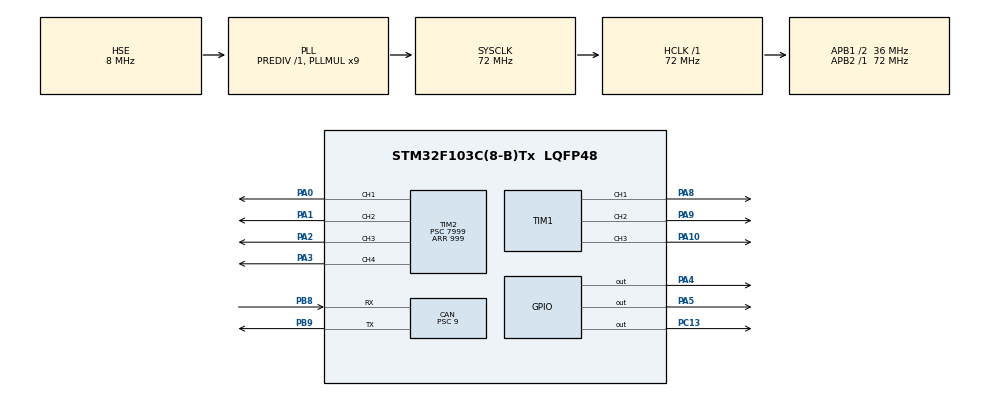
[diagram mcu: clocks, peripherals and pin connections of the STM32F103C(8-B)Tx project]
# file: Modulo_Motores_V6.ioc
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CAN.BS1=CAN_BS1_13TQ
CAN.BS2=CAN_BS2_2TQ
CAN.CalculateTimeBit=4000
CAN.CalculateTimeQuantum=250.0
CAN.Prescaler=9
Mcu.Family=STM32F1
Mcu.Name=STM32F103C(8-B)Tx
Mcu.Package=LQFP48
NVIC.PriorityGroup=NVIC_PRIORITYGROUP_4
NVIC.TIM2_IRQn=true\:0\:0\:false\:false\:true\:true\:true
NVIC.USB_LP_CAN1_RX0_IRQn=true\:0\:0\:false\:false\:true\:true\:true
PA0-WKUP.Signal=S_TIM2_CH1_ETR
PA1.Signal=S_TIM2_CH2
PA10.Signal=S_TIM1_CH3
PA2.Signal=S_TIM2_CH3
PA3.Signal=S_TIM2_CH4
PA4.Signal=GPIO_Output
PA5.Signal=GPIO_Output
PA8.Signal=S_TIM1_CH1
PA9.Signal=S_TIM1_CH2
PB8.Mode=Master
PB8.Signal=CAN_RX
PB9.Mode=Master
PB9.Signal=CAN_TX
PC13-TAMPER-RTC.Signal=GPIO_Output
PD0-OSC_IN.Mode=HSE-External-Oscillator
PD0-OSC_IN.Signal=RCC_OSC_IN
PD1-OSC_OUT.Mode=HSE-External-Oscillator
PD1-OSC_OUT.Signal=RCC_OSC_OUT
ProjectManager.HeapSize=0x200
ProjectManager.StackSize=0x400
ProjectManager.TargetToolchain=TrueSTUDIO
RCC.AHBFreq_Value=72000000
RCC.APB1CLKDivider=RCC_HCLK_DIV2
RCC.APB1Freq_Value=36000000
RCC.APB1TimFreq_Value=72000000
RCC.APB2Freq_Value=72000000
RCC.APB2TimFreq_Value=72000000
RCC.HCLKFreq_Value=72000000
RCC.PLLMUL=RCC_PLL_MUL9
RCC.PLLSourceVirtual=RCC_PLLSOURCE_HSE
RCC.SYSCLKFreq_VALUE=72000000
RCC.SYSCLKSource=RCC_SYSCLKSOURCE_PLLCLK
RCC.USBFreq_Value=72000000
SH.S_TIM1_CH1.0=TIM1_CH1,PWM Generation1 CH1
SH.S_TIM1_CH2.0=TIM1_CH2,PWM Generation2 CH2
SH.S_TIM1_CH3.0=TIM1_CH3,Output Compare3 CH3
SH.S_TIM2_CH1_ETR.0=TIM2_CH1,PWM Generation1 CH1
SH.S_TIM2_CH2.0=TIM2_CH2,PWM Generation2 CH2
SH.S_TIM2_CH3.0=TIM2_CH3,PWM Generation3 CH3
SH.S_TIM2_CH4.0=TIM2_CH4,PWM Generation4 CH4
TIM1.Channel-Output\ Compare3\ CH3=TIM_CHANNEL_3
TIM1.Channel-PWM\ Generation1\ CH1=TIM_CHANNEL_1
TIM1.Channel-PWM\ Generation2\ CH2=TIM_CHANNEL_2
TIM2.Channel-PWM\ Generation1\ CH1=TIM_CHANNEL_1
TIM2.Channel-PWM\ Generation2\ CH2=TIM_CHANNEL_2
TIM2.Channel-PWM\ Generation3\ CH3=TIM_CHANNEL_3
TIM2.Channel-PWM\ Generation4\ CH4=TIM_CHANNEL_4
TIM2.Period=999
TIM2.Prescaler=7999
VP_SYS_VS_ND.Mode=No_Debug
board=custom

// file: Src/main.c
/*

	 .d88888b.  8888888b.  8888888888 888b     d888 888     888  .d8888b.
	d88P" "Y88b 888   Y88b 888        8888b   d8888 888     888 d88P  Y88b
	888     888 888    888 888        88888b.d88888 888     888 Y88b.
	888     888 888   d88P 8888888    888Y88888P888 888     888  "Y888b.
	888     888 8888888P"  888        888 Y888P 888 888     888     "Y88b.
	888     888 888 T88b   888        888  Y8P  888 888     888       "888
	Y88b. .d88P 888  T88b  888        888   "   888 Y88b. .d88P Y88b  d88P
	 "Y88888P"  888   T88b 8888888888 888       888  "Y88888P"   "Y8888P"

  ******************************************************************************
  *        M  O  D  U  L  O     M  O  T  O  R  E  S  -  Versão 7   17/01/2020
  ******************************************************************************

	htim1, TIM_CHANNEL_1, -> Motor de propulsão R
	htim1, TIM_CHANNEL_2  -> Motor de propulsão L

	htim2, TIM_CHANNEL_1, -> Atuador 1
	htim2, TIM_CHANNEL_2, -> Atuador 2
	htim2, TIM_CHANNEL_3, -> Atuador 3
	htim2, TIM_CHANNEL_4, -> Atuador 4

	htim1, TIM_CHANNEL_3  -> LED

	Sensor RPM Motor = B10

	Excurção Máxima - 25 a 250 (0º a 180º) cada unidade é 0.8 graus
	Excurção Pratica - -60º / 0 / + 60º ( 37 / 112 / 187)

	CAN GPIO Configuration
    PB8  -> CAN_RX
    PB9  -> CAN_TX

    PA10  -> LED

	IDs
	0x003 => power on/off
	0x00a => RPM

/* USER CODE BEGIN Header */
/**
  ******************************************************************************
  * @file           : main.c
  * @brief          : Main program body
  ******************************************************************************
  * @attention
  *
  * <h2><center>&copy; Copyright (c) 2020 STMicroelectronics.
  * All rights reserved.</center></h2>
  *
  * This software component is licensed by ST under BSD 3-Clause license,
  * the "License"; You may not use this file except in compliance with the
  * License. You may obtain a copy of the License at:
  *                        opensource.org/licenses/BSD-3-Clause
  *
  ******************************************************************************
  */
/* USER CODE END Header */

#include "main.h"

CAN_HandleTypeDef hcan;

TIM_HandleTypeDef htim1;
TIM_HandleTypeDef htim2;

static CAN_TxHeaderTypeDef TxHeader;
static CAN_RxHeaderTypeDef RxHeader;
uint8_t TxData[8];
uint8_t RxData[8];
uint32_t TxMailbox;

void SystemClock_Config(void);
static void MX_GPIO_Init(void);
static void MX_TIM2_Init(void);
static void MX_CAN_Init(void);
static void MX_TIM1_Init(void);

int main(void)
{

  /* MCU Configuration--------------------------------------------------------*/

  /* Reset of all peripherals, Initializes the Flash interface and the Systick. */
  HAL_Init();
  SystemClock_Config();
  MX_GPIO_Init();
  MX_TIM2_Init();
  MX_CAN_Init();
  MX_TIM1_Init();

  HAL_TIM_Base_Start(&htim1);
  HAL_TIM_PWM_Start(&htim1,TIM_CHANNEL_1); // PWM_L
  HAL_TIM_PWM_Start(&htim1,TIM_CHANNEL_2); // PWM_R
  HAL_TIM_PWM_Start(&htim1,TIM_CHANNEL_3); // LED VERDE

  HAL_TIM_Base_Start(&htim2);
  HAL_TIM_PWM_Start(&htim2,TIM_CHANNEL_1); //A1
  HAL_TIM_PWM_Start(&htim2,TIM_CHANNEL_2); //A2
  HAL_TIM_PWM_Start(&htim2,TIM_CHANNEL_3); //A3
  HAL_TIM_PWM_Start(&htim2,TIM_CHANNEL_4); //A4

  /* Infinite loop */
  /* USER CODE BEGIN WHILE */
  int pwm=0;

  while (1)
  {

	  if (RxHeader.StdId == 0x003){ // green

			__HAL_TIM_SET_COMPARE(&htim2, TIM_CHANNEL_1, RxData[0]); //update pwm value
			__HAL_TIM_SET_COMPARE(&htim2, TIM_CHANNEL_2, RxData[1]); //update pwm value
			__HAL_TIM_SET_COMPARE(&htim2, TIM_CHANNEL_3, RxData[2]); //update pwm value
			__HAL_TIM_SET_COMPARE(&htim2, TIM_CHANNEL_4, RxData[3]); //update pwm value
			__HAL_TIM_SET_COMPARE(&htim1, TIM_CHANNEL_2, RxData[4]); //update pwm value
			HAL_Delay(5);  //hold for 400m
		  }

  }
  /* USER CODE END 3 */
}

void SystemClock_Config(void)
{
  RCC_OscInitTypeDef RCC_OscInitStruct = {0};
  RCC_ClkInitTypeDef RCC_ClkInitStruct = {0};

  /** Initializes the CPU, AHB and APB busses clocks
  */
  RCC_OscInitStruct.OscillatorType = RCC_OSCILLATORTYPE_HSE;
  RCC_OscInitStruct.HSEState = RCC_HSE_ON;
  RCC_OscInitStruct.HSEPredivValue = RCC_HSE_PREDIV_DIV1;
  RCC_OscInitStruct.HSIState = RCC_HSI_ON;
  RCC_OscInitStruct.PLL.PLLState = RCC_PLL_ON;
  RCC_OscInitStruct.PLL.PLLSource = RCC_PLLSOURCE_HSE;
  RCC_OscInitStruct.PLL.PLLMUL = RCC_PLL_MUL9;
  if (HAL_RCC_OscConfig(&RCC_OscInitStruct) != HAL_OK)
  {
    Error_Handler();
  }
  /** Initializes the CPU, AHB and APB busses clocks
  */
  RCC_ClkInitStruct.ClockType = RCC_CLOCKTYPE_HCLK|RCC_CLOCKTYPE_SYSCLK
                              |RCC_CLOCKTYPE_PCLK1|RCC_CLOCKTYPE_PCLK2;
  RCC_ClkInitStruct.SYSCLKSource = RCC_SYSCLKSOURCE_PLLCLK;
  RCC_ClkInitStruct.AHBCLKDivider = RCC_SYSCLK_DIV1;
  RCC_ClkInitStruct.APB1CLKDivider = RCC_HCLK_DIV2;
  RCC_ClkInitStruct.APB2CLKDivider = RCC_HCLK_DIV1;

  if (HAL_RCC_ClockConfig(&RCC_ClkInitStruct, FLASH_LATENCY_2) != HAL_OK)
  {
    Error_Handler();
  }
}

static void MX_CAN_Init(void)
{

  hcan.Instance = CAN1;
  hcan.Init.Prescaler = 9;
  hcan.Init.Mode = CAN_MODE_NORMAL;
  hcan.Init.SyncJumpWidth = CAN_SJW_1TQ;
  hcan.Init.TimeSeg1 = CAN_BS1_13TQ;
  hcan.Init.TimeSeg2 = CAN_BS2_2TQ;
  hcan.Init.TimeTriggeredMode = DISABLE;
  hcan.Init.AutoBusOff = DISABLE;
  hcan.Init.AutoWakeUp = DISABLE;
  hcan.Init.AutoRetransmission = DISABLE;
  hcan.Init.ReceiveFifoLocked = DISABLE;
  hcan.Init.TransmitFifoPriority = DISABLE;
  if (HAL_CAN_Init(&hcan) != HAL_OK)
  {
    Error_Handler();
  }

  if (HAL_CAN_ActivateNotification(&hcan, CAN_IT_RX_FIFO0_MSG_PENDING) != HAL_OK)
  {
	Error_Handler();
  }

  /* Configure the CAN Filter */
  CAN_FilterTypeDef  sFilterConfig;
  sFilterConfig.FilterBank = 0;
  sFilterConfig.FilterMode = CAN_FILTERMODE_IDMASK;
  sFilterConfig.FilterScale = CAN_FILTERSCALE_32BIT;
  sFilterConfig.FilterIdHigh     = 0x000<<5; //0x000
  sFilterConfig.FilterIdLow      = 0x0000;
  sFilterConfig.FilterMaskIdHigh = 0x700<<5; // mascara que filtra
  sFilterConfig.FilterMaskIdLow  = 0x0000;
  sFilterConfig.FilterFIFOAssignment = CAN_RX_FIFO0;
  sFilterConfig.FilterActivation = ENABLE;
  sFilterConfig.SlaveStartFilterBank = 14;
  if (HAL_CAN_ConfigFilter(&hcan, &sFilterConfig) != HAL_OK)
  {
    /* Filter configuration Error */
    Error_Handler();
  }

  /* Configure Transmission process */
  TxHeader.StdId = 0x001;
  TxHeader.ExtId = 0x001;
  TxHeader.RTR = CAN_RTR_DATA;
  TxHeader.IDE = CAN_ID_STD;
  TxHeader.DLC = 8;
  TxHeader.TransmitGlobalTime = DISABLE;

  /* Start the CAN peripheral */
  if (HAL_CAN_Start(&hcan) != HAL_OK)
  {
    /* Start Error */
    Error_Handler();
  }

}

static void MX_TIM1_Init(void)
{

  TIM_MasterConfigTypeDef sMasterConfig = {0};
  TIM_OC_InitTypeDef sConfigOC = {0};
  TIM_BreakDeadTimeConfigTypeDef sBreakDeadTimeConfig = {0};

  htim1.Instance = TIM1;
  htim1.Init.Prescaler = 11;
  htim1.Init.CounterMode = TIM_COUNTERMODE_UP;
  htim1.Init.Period = 300;
  htim1.Init.ClockDivision = TIM_CLOCKDIVISION_DIV1;
  htim1.Init.RepetitionCounter = 0;
  htim1.Init.AutoReloadPreload = TIM_AUTORELOAD_PRELOAD_DISABLE;
  if (HAL_TIM_PWM_Init(&htim1) != HAL_OK)
  {
    Error_Handler();
  }
  sMasterConfig.MasterOutputTrigger = TIM_TRGO_RESET;
  sMasterConfig.MasterSlaveMode = TIM_MASTERSLAVEMODE_DISABLE;
  if (HAL_TIMEx_MasterConfigSynchronization(&htim1, &sMasterConfig) != HAL_OK)
  {
    Error_Handler();
  }
  sConfigOC.OCMode = TIM_OCMODE_PWM1;
  sConfigOC.Pulse = 0;
  sConfigOC.OCPolarity = TIM_OCPOLARITY_HIGH;
  sConfigOC.OCNPolarity = TIM_OCNPOLARITY_HIGH;
  sConfigOC.OCFastMode = TIM_OCFAST_DISABLE;
  sConfigOC.OCIdleState = TIM_OCIDLESTATE_RESET;
  sConfigOC.OCNIdleState = TIM_OCNIDLESTATE_RESET;
  if (HAL_TIM_PWM_ConfigChannel(&htim1, &sConfigOC, TIM_CHANNEL_1) != HAL_OK)
  {
    Error_Handler();
  }
  if (HAL_TIM_PWM_ConfigChannel(&htim1, &sConfigOC, TIM_CHANNEL_2) != HAL_OK)
  {
    Error_Handler();
  }
  if (HAL_TIM_PWM_ConfigChannel(&htim1, &sConfigOC, TIM_CHANNEL_3) != HAL_OK)
  {
    Error_Handler();
  }
  sBreakDeadTimeConfig.OffStateRunMode = TIM_OSSR_DISABLE;
  sBreakDeadTimeConfig.OffStateIDLEMode = TIM_OSSI_DISABLE;
  sBreakDeadTimeConfig.LockLevel = TIM_LOCKLEVEL_OFF;
  sBreakDeadTimeConfig.DeadTime = 0;
  sBreakDeadTimeConfig.BreakState = TIM_BREAK_DISABLE;
  sBreakDeadTimeConfig.BreakPolarity = TIM_BREAKPOLARITY_HIGH;
  sBreakDeadTimeConfig.AutomaticOutput = TIM_AUTOMATICOUTPUT_DISABLE;
  if (HAL_TIMEx_ConfigBreakDeadTime(&htim1, &sBreakDeadTimeConfig) != HAL_OK)
  {
    Error_Handler();
  }
  HAL_TIM_MspPostInit(&htim1);

}

static void MX_TIM2_Init(void)
{

  TIM_MasterConfigTypeDef sMasterConfig = {0};
  TIM_OC_InitTypeDef sConfigOC = {0};

  htim2.Instance = TIM2;
  htim2.Init.Prescaler = 799;
  htim2.Init.CounterMode = TIM_COUNTERMODE_UP;
  htim2.Init.Period = 1800;
  htim2.Init.ClockDivision = TIM_CLOCKDIVISION_DIV1;
  htim2.Init.AutoReloadPreload = TIM_AUTORELOAD_PRELOAD_DISABLE;
  if (HAL_TIM_PWM_Init(&htim2) != HAL_OK)
  {
    Error_Handler();
  }
  sMasterConfig.MasterOutputTrigger = TIM_TRGO_RESET;
  sMasterConfig.MasterSlaveMode = TIM_MASTERSLAVEMODE_DISABLE;
  if (HAL_TIMEx_MasterConfigSynchronization(&htim2, &sMasterConfig) != HAL_OK)
  {
    Error_Handler();
  }
  sConfigOC.OCMode = TIM_OCMODE_PWM1;
  sConfigOC.Pulse = 0;
  sConfigOC.OCPolarity = TIM_OCPOLARITY_HIGH;
  sConfigOC.OCFastMode = TIM_OCFAST_DISABLE;
  if (HAL_TIM_PWM_ConfigChannel(&htim2, &sConfigOC, TIM_CHANNEL_1) != HAL_OK)
  {
    Error_Handler();
  }
  if (HAL_TIM_PWM_ConfigChannel(&htim2, &sConfigOC, TIM_CHANNEL_2) != HAL_OK)
  {
    Error_Handler();
  }
  if (HAL_TIM_PWM_ConfigChannel(&htim2, &sConfigOC, TIM_CHANNEL_3) != HAL_OK)
  {
    Error_Handler();
  }
  if (HAL_TIM_PWM_ConfigChannel(&htim2, &sConfigOC, TIM_CHANNEL_4) != HAL_OK)
  {
    Error_Handler();
  }
  HAL_TIM_MspPostInit(&htim2);

}

static void MX_GPIO_Init(void)
{
  GPIO_InitTypeDef GPIO_InitStruct = {0};

  /* GPIO Ports Clock Enable */
  __HAL_RCC_GPIOC_CLK_ENABLE();
  __HAL_RCC_GPIOD_CLK_ENABLE();
  __HAL_RCC_GPIOA_CLK_ENABLE();
  __HAL_RCC_GPIOB_CLK_ENABLE();

  /*Configure GPIO pin Output Level */
  HAL_GPIO_WritePin(GPIOC, GPIO_PIN_13, GPIO_PIN_SET);

  /*Configure GPIO pin : PC13 */
  GPIO_InitStruct.Pin = GPIO_PIN_13;
  GPIO_InitStruct.Mode = GPIO_MODE_OUTPUT_PP;
  GPIO_InitStruct.Pull = GPIO_NOPULL;
  GPIO_InitStruct.Speed = GPIO_SPEED_FREQ_LOW;
  HAL_GPIO_Init(GPIOC, &GPIO_InitStruct);

  /*Configure GPIO pin : PB12 */
  GPIO_InitStruct.Pin = GPIO_PIN_12;
  GPIO_InitStruct.Mode = GPIO_MODE_OUTPUT_PP;
  GPIO_InitStruct.Pull = GPIO_NOPULL;
  GPIO_InitStruct.Speed = GPIO_SPEED_FREQ_LOW;
  HAL_GPIO_Init(GPIOB, &GPIO_InitStruct);

  /*Configure GPIO pin : PB13 */
  GPIO_InitStruct.Pin = GPIO_PIN_13;
  GPIO_InitStruct.Mode = GPIO_MODE_OUTPUT_PP;
  GPIO_InitStruct.Pull = GPIO_NOPULL;
  GPIO_InitStruct.Speed = GPIO_SPEED_FREQ_LOW;
  HAL_GPIO_Init(GPIOB, &GPIO_InitStruct);

  /*Configure GPIO pin : PB14 */
  GPIO_InitStruct.Pin = GPIO_PIN_14;
  GPIO_InitStruct.Mode = GPIO_MODE_OUTPUT_PP;
  GPIO_InitStruct.Pull = GPIO_NOPULL;
  GPIO_InitStruct.Speed = GPIO_SPEED_FREQ_LOW;
  HAL_GPIO_Init(GPIOB, &GPIO_InitStruct);

}

void HAL_CAN_RxFifo0MsgPendingCallback(CAN_HandleTypeDef *hcan)
{
  //HAL_GPIO_TogglePin(GPIOC,GPIO_PIN_13);
  /* Get RX message */
  if (HAL_CAN_GetRxMessage(hcan, CAN_RX_FIFO0, &RxHeader, RxData) != HAL_OK)
  {

    Error_Handler();
  }
}

void Error_Handler(void)
{
  /* USER CODE BEGIN Error_Handler_Debug */
  /* User can add his own implementation to report the HAL error return state */
	HAL_Delay(100);
  /* USER CODE END Error_Handler_Debug */
}

/************************ (C) COPYRIGHT STMicroelectronics *****END OF FILE****/
